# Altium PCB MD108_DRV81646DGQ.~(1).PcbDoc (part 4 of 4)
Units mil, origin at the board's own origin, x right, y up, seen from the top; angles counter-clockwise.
Board outline 6002 x 2931.52 mil, 4 copper layers (Top Layer, Mid-Layer 1, Mid-Layer 2, Bottom Layer), stack 92.712 mil thick; 251 components, 140 nets, 776 pads, 239 vias.
Unrouted connection lines stored in the file: 111.

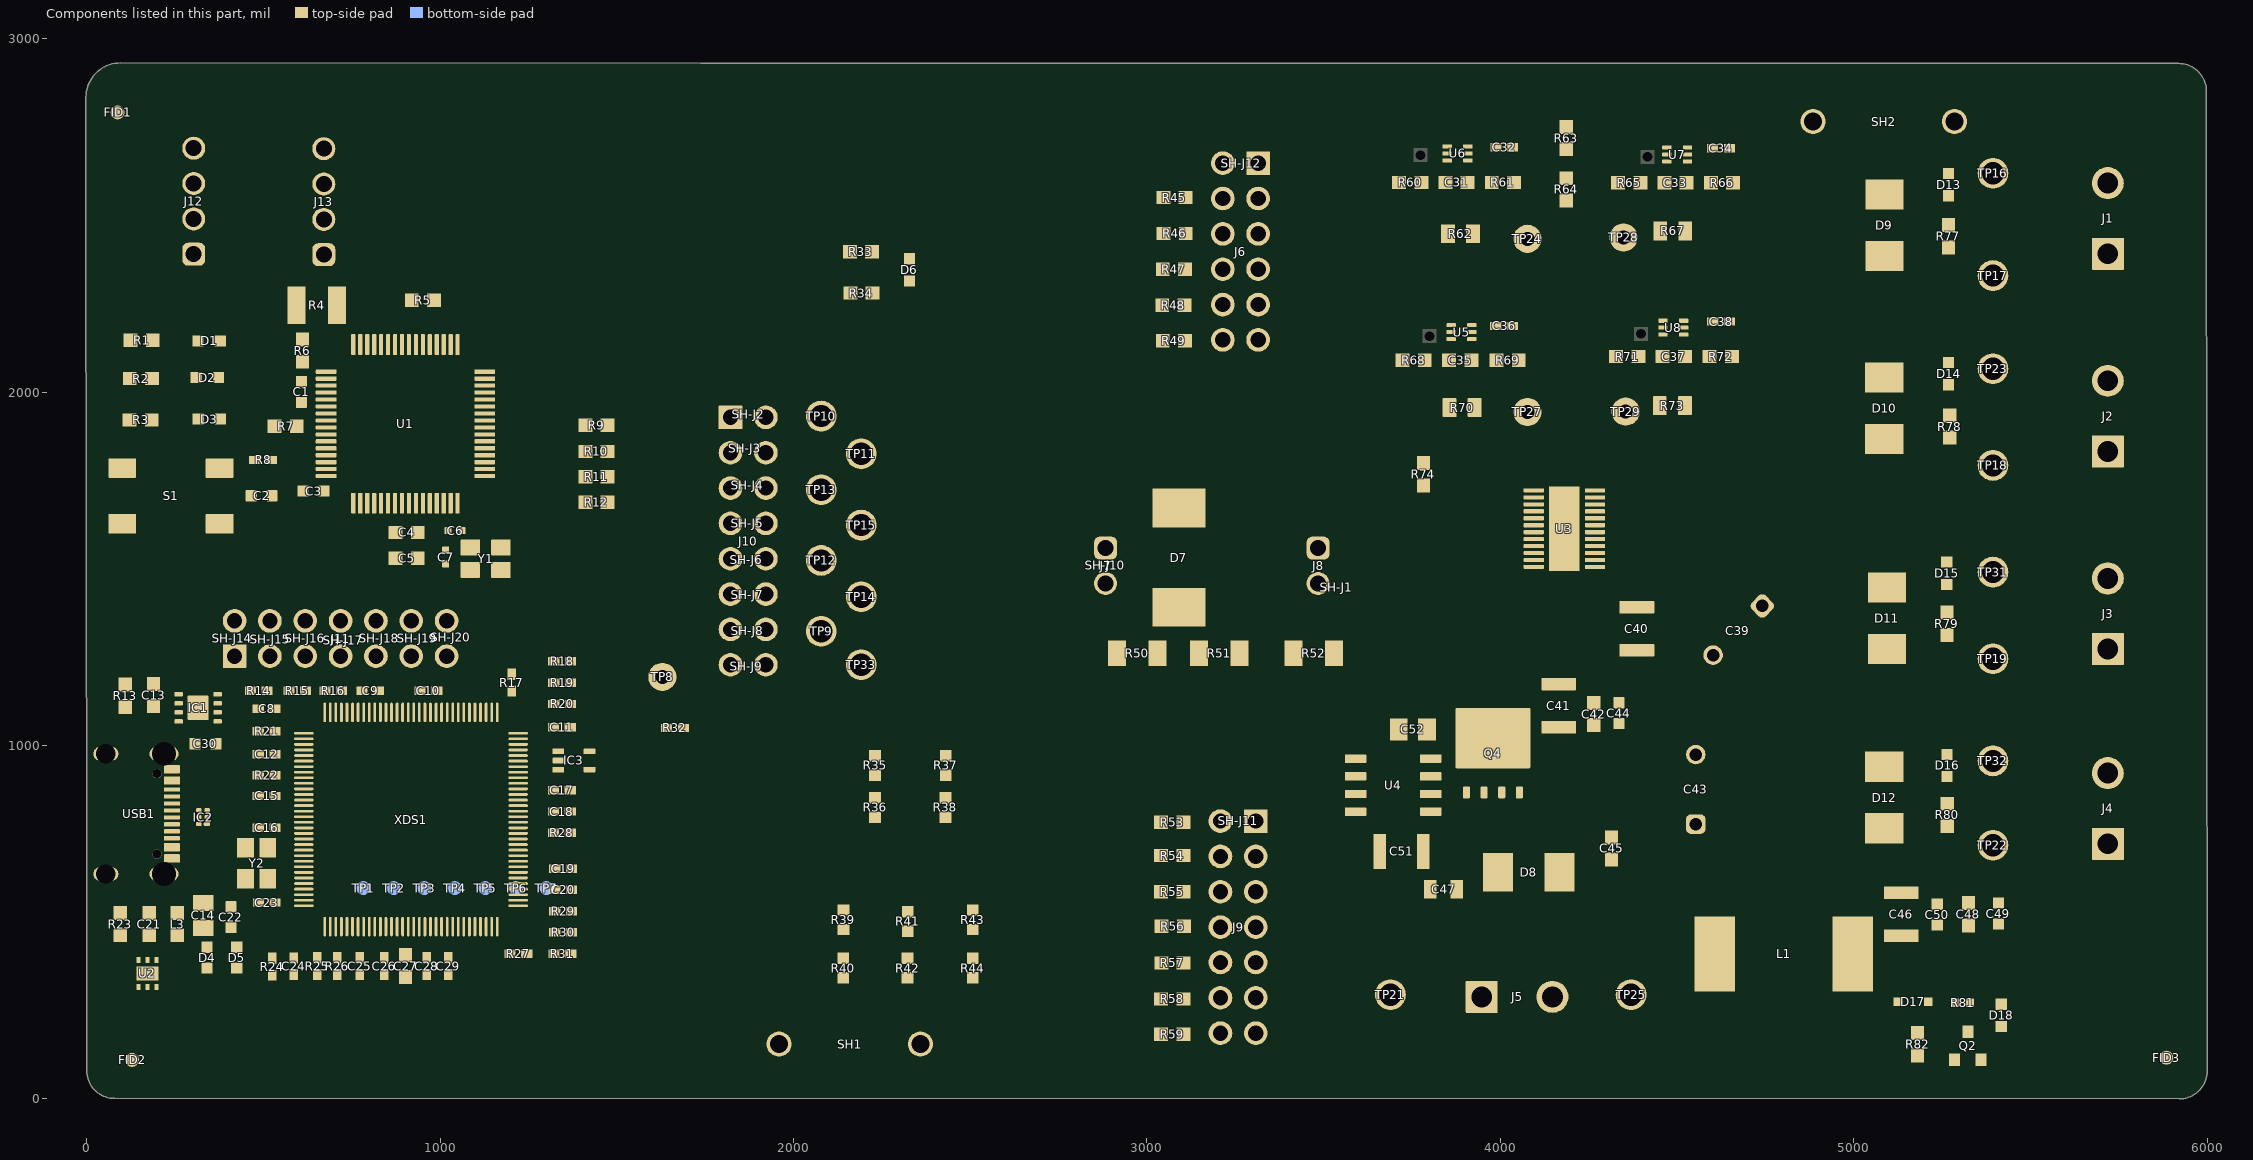
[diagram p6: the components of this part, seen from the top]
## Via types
v1: diameter 30, hole 16, Top Layer to Bottom Layer, tented both sides, 89 vias
v2: diameter 20, hole 8, Top Layer to Bottom Layer, tented both sides, 47 vias
v3: diameter 19.68, hole 7.87, Top Layer to Bottom Layer, tented both sides, 35 vias
v4: diameter 24, hole 12, Top Layer to Bottom Layer, tented both sides, 14 vias
v5: diameter 24, hole 7.87, Top Layer to Bottom Layer, tented both sides, 11 vias
v6: diameter 30, hole 15, Top Layer to Bottom Layer, tented both sides, 10 vias
v7: diameter 28, hole 14, Top Layer to Bottom Layer, tented both sides, 9 vias
v8: diameter 19.68, hole 7.87, Top Layer to Bottom Layer, 6 vias
v9: diameter 24, hole 8, Top Layer to Bottom Layer, tented both sides, 5 vias
v10: diameter 30, hole 14, Top Layer to Bottom Layer, tented both sides, 4 vias
v11: diameter 24, hole 11.81, Top Layer to Bottom Layer, tented both sides, 4 vias
v12: diameter 36, hole 18.29, Top Layer to Bottom Layer, tented both sides, 2 vias
v13: diameter 30, hole 15.75, Top Layer to Bottom Layer, tented both sides, 2 vias
v14: diameter 34, hole 16, Top Layer to Bottom Layer, tented both sides, 1 vias

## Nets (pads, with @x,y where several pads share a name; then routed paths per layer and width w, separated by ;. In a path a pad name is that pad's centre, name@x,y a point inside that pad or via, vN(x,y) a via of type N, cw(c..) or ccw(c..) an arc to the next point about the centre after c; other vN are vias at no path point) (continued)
copper on no net:
  other v2: 659.61,555.57 658.61,624.57

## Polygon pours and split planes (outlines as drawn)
GND on Top Layer "TOP_LAYER_GND_P439" (solid, remove dead copper, pour order 439): -13.71,2930.49 5964.99,2930.49 5964.99,-4.44 5948.53,-20.91 5936.7,-9.09 -35.01,-9.09 -35.01,2956.1
XDS_VCC on Top Layer "TOP_LAYER_XDS_VCC_P437" (solid, remove dead copper, pour order 437): 334.81,113.75 375.02,76.57 397.07,76.57 1314.1,76.57 1370.1,132.57 1370.1,334.15 1505.6,334.15 1548.02,376.57 1544.02,380.57 1544.02,1275.57 334.81,1275.57
VBAT on Top Layer "TOP_LAYER_VBAT_P436" (solid, remove dead copper, pour order 436): 3858.01,798.22 3770.91,798.54 3770.28,825.45 3857.82,825.45 3857.82,903.99 4032.52,903.99 4032.52,96.59 3857.82,96.59
no net on Top Layer "TOP_LAYER_NONET_P435" (solid, remove dead copper, pour order 435): 561.98,1466.48 567.61,1472.12 567.61,1611.68 481.47,1611.68 453.04,1583.25 453.04,1466.48
RSLEW/CNTL_GND/HiZ/VDD on Top Layer "TOP_LAYER_RSLEW/CNTL_GND/HIZ/VDD_P434" (solid, remove dead copper, pour order 434): 1451.8,1933.34 1500.73,1933.34 1500.73,1666.3 1451.8,1666.3
3V3_MCU on Top Layer "TOP_LAYER_3V3_MCU_P433" (solid, remove dead copper, pour order 433): 349.91,1879.24 349.07,1880.08 349.07,1948.64 427.42,1948.64 427.42,1899.21 407.45,1879.24 349.27,1879.24
OUT1 on Top Layer "TOP_LAYER_OUT1_P432" (solid, remove dead copper, pour order 432): 5932.98,2460.76 5931.09,2458.86 5356.79,2458.86 5337.83,2439.91 4941.64,2436.66 4875.32,2370.34 4875.04,2265.21 4875.32,2261.57 4875.36,2257.95 4865.14,2175.94 4472.34,1772.53 4474.36,1711.78 4431.43,1663.93 4455.21,1652.83 4494.59,1695.6 4545.21,1692.56 4987.74,2132.16 4989.58,2175.39 4992.93,2254.2 5931.09,2257.95 5931.09,2453.18 5932.98,2455.07
OUT2 on Top Layer "TOP_LAYER_OUT2_P430" (solid, remove dead copper, pour order 430): 5931.41,1930.74 5929.51,1928.85 5355.21,1928.85 5336.26,1909.89 4931.69,1906.57 4641.25,1722.03 4530.3,1642.71 4448.32,1643.7 4450.7,1616.41 4522.08,1615.64 4648.75,1616.69 4688.95,1627.78 4788.15,1674.34 4866.2,1727.94 4873.78,1727.94 5929.51,1727.94 5929.51,1923.16 5931.41,1925.06
OUT3 on Top Layer "TOP_LAYER_OUT3_P429" (solid, remove dead copper, pour order 429): 5933.38,1369.76 5931.49,1367.86 5357.19,1367.86 5338.23,1348.91 5061.86,1353.05 5010.83,1392.95 4926.82,1488.09 4785.08,1618.7 4670.73,1614.18 4363.89,1614.18 4363.89,1577.93 4638.41,1576.13 4899.49,1309.95 4875.72,1279.34 4875.72,1203.04 4875.44,1203.32 4926.82,1166.95 5931.49,1166.95 5931.49,1362.18 5933.38,1364.07
OUT4 on Top Layer "TOP_LAYER_OUT4_P395" (solid, remove dead copper, pour order 395): 5940.62,828.8 5938.73,826.9 5364.43,826.9 5345.47,807.95 5177.4,807.66 4525.71,1581.53 4413.98,1581.53 4414.9,1559.43 4621.1,1299.44 4931.54,786.95 4931.54,667.96 5022.97,625.99 5938.73,625.99 5938.73,821.21 5940.62,823.11
PI_IN on Top Layer "TOP_LAYER_PI_IN_P392" (solid, remove dead copper, pour order 392): 4153.62,953.28 3764.87,953.28 3764.87,1118.37 4103.75,1114.49 4116.16,1084.38 4141.08,1085.43 4348.7,1084.38 4348.7,869.54 4585.45,862.76 4703.77,778.73 4703.77,268.87 4675.69,240.79 4674.04,242.44 4522.11,242.44 4522.11,678.43 4470.91,729.62 4153.62,729.62
VM on Top Layer "TOP_LAYER_VM_P389" (solid, remove dead copper, pour order 389): 4941.98,511.49 4949.02,511.49 5695,511.49 5695,311.71 5682.83,299.55 4935.58,299.55 4935.58,508.29 4941.98,514.7 4942.62,514.7
no net on Top Layer "TOP_LAYER_NONET_P388" (solid, remove dead copper, pour order 388): 5087.71,604.14 5085.71,604.14 5447.49,604.14 5447.49,529.45 5441.36,523.33 5435.85,528.84 5082.65,528.84 5082.65,603.52 5082.04,604.14 5088.77,604.14
GND on Mid-Layer 2 "MID-LAYER_2_GND_P438" (solid, remove dead copper, pour order 438): -2.48,15.85 -2.48,2931.38 5997.52,2931.38 5997.52,15.85
VM on Mid-Layer 2 "MID-LAYER_2_VM_P427" (solid, remove dead copper, pour order 427): 5035.66,911.02 5034.64,910 4755.89,910 4755.89,1026.46 5086.33,1026.46 5094.19,1034.32 5094.19,911.02 5036.49,911.02 5035.66,911.85
VM on Bottom Layer "BOTTOM_LAYER_VM_P408" (solid, remove dead copper, pour order 408): 5485.78,2702.64 5486.92,2701.5 5650.26,2701.5 5650.26,306.86 5643.46,300.05 5642.32,301.18 5488.05,301.18 5488.05,2699.23 5486.92,2700.37
GND on Bottom Layer "BOTTOM_LAYER_GND_P413" (solid, remove dead copper, pour order 413): -26.36,2962.01 5965.24,2962.01 5973.64,2970.42 5973.64,-16.53 -26.36,-16.53
3V3_MCU on Mid-Layer 1 "MID-LAYER_1_3V3_MCU_P401" (solid, remove dead copper, pour order 401): 1685.54,1312.16 1749.88,1312.12 1750.94,1887.98 1864.7,1886.86 1867.24,1971.02 1654.9,1968.19 1654.9,1444.4 1442.8,1444.4 1245.24,1444.4 576.37,1444.4 580.16,1908.27 576.37,1908.27 507.13,1965.83 36.1,1964.87 36.1,1430.53 154.46,1312.16
GND on Mid-Layer 1 "MID-LAYER_1_GND_P421" (solid, remove dead copper, pour order 421): -33.06,-33.22 -33.06,2906.78 5966.94,2906.78 5966.94,-33.22

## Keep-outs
Keep-Out Layer:
  lines w20: -5.09,2930 5994.91,2930 6000,0 0,0 0,613.39 0,939.17 0,2930
  text ".Layer_Name" at 563.61,-858.49 h60

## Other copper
Top Layer:
  region net XDS_VCC: 1070.97,434.31 1063.97,434.31 1063.97,594.25 1066.81,594.25 1070.97,594.25 1070.97,496.56
  region net XDS_VCC: 1144.61,779.57 1167.61,779.57 1214.61,779.57 1214.61,785.57 1213.61,786.57 1144.61,786.57
  region net XDS_VCC: 1220.61,967.57 1144.61,967.57 1144.61,975.57 1220.61,975.57
  region net XDS_VCC: 1220.61,936.57 1144.61,936.57 1144.61,944.57 1146.61,944.57 1220.61,944.57
  region net XDS_VCC: 1144.61,637.57 1166.61,637.57 1273.61,637.57 1273.61,664.57 1273.61,660.57 1267.61,660.57 1144.61,660.57
  pour cut-out: 492.09,368.44 664.43,368.44 664.43,545.35 492.09,545.35
  pour cut-out: 1161.61,442.57 740.61,442.57 740.61,525.57 747.61,532.57 1160.61,532.57 1161.61,531.57
  pour cut-out: 659.61,626.57 659.61,940.57 569.61,940.57 569.61,639.57 582.61,626.57
  pour cut-out: 1193.61,544.57 1263.69,544.57 1266.67,547.55 1266.61,547.61 1266.61,1048.57 1259.61,1055.57 1188.61,1055.57 1175,1041.95 1175,557.16
  region net XDS_VCC: 929.61,471.51 929.61,551.57 921.61,551.57 921.61,471.51
  region net XDS_VCC: 611.61,810.57 611.61,818.57 714.61,818.57 714.61,811.57 714.61,810.57
  pour cut-out: 413.54,661.1 468.16,661.1 459.74,669.53 459.74,676.6 413.54,676.6
  region net XDS_VCC: 937.61,1096.57 937.61,1001.57 944.61,1001.57 944.61,1096.57
  region net XDS_VCC: 1063.61,1096.57 1063.61,995.57 1070.61,995.57 1070.61,1096.57
  region net XDS_VCC: 858.61,1001.57 882.61,1001.57 882.61,1166.57 858.61,1166.57
  pour cut-out: 1182.61,1117.57 1182.61,1060.87 1168.95,1048.57 824.61,1048.57 824.61,1140.57 1169.61,1140.57
  text ".Layer_Name" at 563.61,-858.49 h60
Mid-Layer 1:
  pour cut-out: 403.61,544.57 403.61,791.57 538.61,791.57 538.61,740.34 578.34,740.34 586.61,732.07 586.61,606.57 577.61,597.57 538.61,597.57 538.61,544.57
Mid-Layer 2:
  pour cut-out: 403.61,544.57 537.61,544.57 538.61,545.57 538.61,597.57 577.61,597.57 586.61,606.57 586.61,732.06 578.34,740.34 538.61,740.34 538.61,791.57 403.61,791.57
Bottom Layer:
  text ".Layer_Name" at 563.61,-858.49 h60

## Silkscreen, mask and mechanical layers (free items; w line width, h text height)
Top Overlay:
  drawing of 1235 lines, arcs and shapes, not listed
  text "GND" at 4742.54,2813.6 h106.3
  text "AUXILARY PINOUTS" at 152.04,2798.29 h60
  text "DRV81646DGQ" at 1949.61,2778.7 h80
  text "CSA 3" at 4288.24,2775.8 h60
  text "CSA 2" at 3667.03,2771.86 h60
  text "MSPM0" at 1516.1,2741.76 h80
  text "Cut Off Delay / INRUSH" at 2650.85,2741.31 h65
  text "VM" at 5351.48,2696.87 h70
  text "PB24" at 386.48,2663.6 h59.06
  text "PB13" at 788.92,2661.85 h59.06
  text "INRUSH" at 2684.64,2639.68 h60
  text "(OUT1)" at 4969.67,2634.19 h60
  text "PB25" at 386.48,2569.91 h59.06
  text "PB12" at 788.92,2568.16 h59.06
  text "DISABLED" at 2664.34,2525.61 h60
  text "nFAULT LED" at 2077.59,2522.05 h60
  text "DRV81646DGQEVM" at 1011.5,2483.86 h120
  text "PA0" at 386.48,2462.17 h59.06
  text "PB11" at 788.92,2460.42 h59.06
  text "0.5 ms" at 2664.48,2430.56 h60
  text "SRC2" at 3661.34,2408.93 h59.06
  text "SRC3" at 4551.72,2406.18 h59.06
  text "OUT1" at 5319.12,2405.32 h70
  text "PA1" at 386.48,2362.24 h59.06
  text "PB10" at 788.92,2360.49 h59.06
  text "MD108.PCB_Rev" at 1223.49,2352.95 h108.27
  text "1 ms" at 2664.48,2316.49 h60
  text "CSA 4" at 4283.04,2279.01 h60
  text "CSA 1" at 3677.28,2273.39 h60
  text "LED STATUS" at 40.94,2233.41 h60
  text "1.5 ms" at 2664.48,2207.85 h60
  text "OUT1" at 5483.29,2184.19 h100
  text "MCU_STATUS" at 93.8,2170.54 h30
  text "VM" at 5351.48,2137.57 h70
  text "2 ms" at 2664.48,2110.08 h60
  text "(OUT2)" at 4965.74,2089.68 h60
  text "GUI_STATUS" at 105.58,2078.93 h30
  text "3V3_STATUS" at 109.44,1965.67 h30
  text "3V3" at 2270.42,1917.19 h98.43
  text "SRC4" at 4556.72,1914.36 h59.06
  text "SRC1" at 3669.3,1907.06 h59.06
  text "DECAY MODES" at 2795.9,1900.5 h60
  text "OUT2" at 5329.87,1867.44 h70
  text "VCLAMP" at 3189.04,1805.81 h30
  text "nFAULT" at 2267.76,1794.15 h98.43
  text "FAST" at 2805.43,1787.62 h100
  text "SLOW" at 3397.43,1787.62 h100
  text "SDI/IN1" at 2270.42,1691.81 h98.43
  text "OUT2" at 5483.29,1628.22 h100
  text "SCLK/IN2" at 2271.85,1585.28 h98.43
  text "VM" at 5349.1,1563.99 h70
  text "(OUT3)" at 4962.21,1497.71 h60
  text "nSCS/IN3" at 2270.64,1477.34 h98.43
  text "NRST" at 1368.35,1421.15 h80 r90
  text "SWDIO" at 1448.78,1421.15 h80 r90
  text "SWCLK" at 1547.92,1421.15 h80 r90
  text "DRV81646" at 4028.98,1419.88 h40
  text "RXD>>" at 630.53,1411.86 h80 r90
  text "TXD <<" at 770.68,1408.57 h80 r90
  text "SDO/IN4" at 2271.75,1376.33 h98.43
  text "Target" at 1116.49,1324.37 h45
  text "OUT3" at 5331.06,1318.85 h70
  text "RSLEW/CNTL" at 2275.14,1273.35 h98.43
  text "Debugger" at 1099.6,1238.25 h45
  text "GND" at 2275.58,1179.22 h98.43
  text "GND" at 2869.9,1123.68 h30
  text "VM" at 3304.55,1122.06 h30
  text "OUT3" at 5483.29,1066 h100
  text "REVISION ID" at 2063.36,1048.16 h60
  text "VM" at 5351.48,1029.68 h70
  text "(OUT4)" at 4963.77,996.73 h60
  text "ILIM" at 2650.85,915.59 h60
  text "REV_ID1" at 2152.02,796.23 h50 r90
  text "REV_ID2" at 2348.35,793.33 h50 r90
  text "OUT4" at 5326.56,792.87 h70
  text "3 A" at 2647.45,754.58 h60
  text "2 A" at 2654.76,668.53 h60
  text "DEVICE ID" at 1963.31,599.4 h60
  text "1 A" at 2656.74,573.5 h60
  text "OUT4" at 5483.29,520.04 h100
  text "1.5 A" at 2658.72,486.38 h60
  text "0.75 A" at 2670.67,376.2 h60
  text "VM LED" at 5089.24,375.34 h60
  text "DEV_ID2" at 2247.32,341.85 h59.06 r90
  text "DEV_ID1" at 2055.1,339.5 h59.06 r90
  text "DEV_ID3" at 2429.1,340.34 h59.06 r90
  text "0.5 A" at 2672.41,271.6 h60
  text "0.25 A" at 2666.16,163.44 h60
  text "GND" at 1710.07,127.45 h106.3
  text "4.5V-65V DC" at 4519.59,88.16 h100
  text "GND" at 4265.93,65.56 h137.8
  text "VBAT" at 3523.59,65.48 h137.8
  text "VM" at 2032.4,-200.22 h30
  text ".Layer_Name" at 891.58,-858.49 h60
Bottom Overlay:
  lines w10: 3423.97,92.93 4602.25,92.93 4602.25,1045.23 3423.97,1045.23 3423.97,92.93
  text "VM" at 5368.99,2694.27 h30
  text "SRC3" at 4413.58,2469.73 h30
  text "SRC2" at 4122.74,2465.21 h30
  text "OUT1" at 5344.47,2399.61 h30
  text "VM" at 5372.74,2134.47 h30
  text "SRC1" at 4134.79,1967.92 h30
  text "SRC4" at 4413.38,1964.55 h30
  text "3V3" at 2170.32,1930.98 h30
  text "OUT2" at 5344.47,1860.7 h30
  text "nFAULT" at 2321.24,1807.86 h30
  text "SDI/IN1" at 2157.42,1712.54 h30
  text "SCLK/IN2" at 2313.36,1613.18 h30
  text "VM" at 5369.26,1555 h30
  text "nSCS/IN3" at 2180.25,1509 h30
  text "SDO/IN4" at 2321.18,1398.21 h30
  text "OUT3" at 5342.16,1307.89 h30
  text "RSLEW/CNTL" at 2181.1,1303.83 h30
  text "VM" at 5366.94,1027.68 h30
  text "OUT4" at 5347.44,783.73 h30
  text "GND" at 799.61,551.56 h50 r90
  text "ITMS" at 885.61,551.57 h50 r90
  text "ITCK" at 971.61,551.57 h50 r90
  text "ITDO" at 1058.61,551.57 h50 r90
  text "ITDI" at 1144.61,551.57 h50 r90
  text "IRSTN" at 1232.61,551.57 h50 r90
  text "XDS_VCC" at 1325.61,551.57 h50 r90
  text "Quick Start / 1. Connect USB, VM, GND, and Load / 2. Open GUI at dev.ti.com/gallery / 3. In the GUI start running each channel." at 3725.19,3.68 h30
  text ".Layer_Name" at 563.61,-858.49 h60
Top Paste:
  text ".Layer_Name" at 563.61,-858.49 h60
Bottom Paste:
  text ".Layer_Name" at 563.61,-858.49 h60
Top Solder:
  text ".Layer_Name" at 563.61,-858.49 h60
  text ".Layer_Name" at 563.61,-858.49 h60
Bottom Solder:
  text ".Layer_Name" at 563.61,-858.49 h60
Drill Guide:
  text ".Layer_Name" at 563.61,-858.49 h60
M1 Board Outline:
  lines w10: 5610.86,2925.07 5918.68,2925.07 ; 5619.56,2925.37 95.27,2931.53 ccw(c95.27,2834.26) -2,2834.26 -2,2516.61 0,675.71 0,613.39 0,80 ccw(c78.74,80) 78.74,1.26 5921.26,0.02 ccw(c5921.26,78.76) 6000,78.76 5998,2851.26 ; 5919.7,2926.62 cw(c5919.7,2847.88) 5998.44,2847.88
  text ".Layer_Name" at 563.61,-858.49 h60
M2 Board Dimensions:
  rectangle: -13.39,-275 111.61,-150
  rectangle: 111.61,-400 486.61,-275
  lines w7: -13.39,-275 986.61,-275 ; 111.61,-400 111.61,-150 ; 236.61,-400 236.61,-150 ; 486.61,-400 486.61,-150 ; 736.61,-400 736.61,-150 ; -13.39,-400 986.61,-400 986.61,-150 -13.39,-150 -13.39,-400
  text ".Layer_Name" at 563.61,-858.49 h60
M3 3D STEP Top:
  text ".Layer_Name" at 563.61,-858.49 h60
M4 3D STEP Bottom:
  text ".Layer_Name" at 563.61,-858.49 h60
M5 Assembly Top:
  lines w10: -305.39,-930.17 6294.61,-930.17 ; -305.39,-726.83 6296.61,-726.83 ; -305.39,-523.5 -305.39,-1133.5 3699.61,-1133.5 6296.61,-1133.5 6296.61,-523.5 -304.89,-523.5 -304.89,-1133.5 1270.61,-1133.5 ; 2159.61,-1133.5 2159.61,-523.5 ; 3426.61,-726.83 3426.61,-523.5 ; 4266.61,-726.83 4266.61,-523.5 ; 4888.61,-1140 4888.61,-937.17
  text "COMPONENTS MARKED 'DNP' SHOULD NOT BE POPULATED." at 1140.11,-318.5 h60
  text "ASSEMBLY VARIANT:" at 1139.61,-434 h60
  text ".VariantName" at 2175.61,-434 h60
  text "PCB VIEWED FROM TOP SIDE" at -241.89,-655.67 h60
  text "BOARD #:" at 2234.61,-655.67 h60
  text ".PRJ_Number" at 2780.11,-655.67 h60
  text "REV:" at 3624.61,-655.67 h60
  text ".PCB_Rev" at 3916.11,-655.67 h60
  text "SVN REV:" at 4462.61,-655.67 h60
  text ".VersionControl_RevNumber" at 4968.61,-655.67 h60
  text "TID #:" at 2234.61,-859 h60
  text ".TID" at 2780.11,-859 h60
  text "PLOT NAME =" at -241.89,-1064.34 h60
  text ".plot_File_Name" at 563.61,-1064.34 h60
  text "GENERATED    :" at 2236.61,-1064.34 h60
  text ".Print_Date" at 3106.11,-1064.34 h60
  text ".Print_Time" at 3835.11,-1064.34 h60
  text "TEXAS INSTRUMENTS" at 5099.61,-1064.34 h60
M6 Assembly Bottom:
  lines w10: -305.89,-727.33 6296.11,-727.33 ; -303.89,-930.67 6296.11,-930.67 ; 1102.11,-1140.5 1102.11,-937.67 ; 1724.11,-727.33 1724.11,-524 ; 2564.11,-727.33 2564.11,-524 ; 3831.11,-1134 3831.11,-524 ; 4720.11,-1134 6295.61,-1134 6295.61,-524 -305.89,-524 -305.89,-1134 2291.11,-1134 6296.11,-1134 6296.11,-524
  text "COMPONENTS MARKED 'DNP' SHOULD NOT BE POPULATED." at 6088.61,-318 h60
  text ".VersionControl_RevNumber" at 10567,-373 h60
  text ".VariantName" at 5044.61,-434 h60
  text "ASSEMBLY VARIANT:" at 6083.61,-434 h60
  text "SVN REV:" at 1528.11,-656.17 h60
  text ".PCB_Rev" at 2074.61,-656.17 h60
  text "REV:" at 2366.11,-656.17 h60
  text ".PRJ_Number" at 3210.61,-656.17 h60
  text "BOARD #:" at 3756.11,-656.17 h60
  text "PCB VIEWED FROM BOTTOM SIDE" at 6232.61,-656.17 h60
  text ".TID" at 3210.61,-859.5 h60
  text "TID #:" at 3756.11,-859.5 h60
  text "TEXAS INSTRUMENTS" at 891.11,-1064.84 h60
  text ".Print_Time" at 2155.61,-1064.84 h60
  text ".Print_Date" at 2884.61,-1064.84 h60
  text "GENERATED    :" at 3754.11,-1064.84 h60
  text ".plot_File_Name" at 5427.11,-1064.84 h60
  text "PLOT NAME =" at 6232.61,-1064.84 h60
M9 Title Sheet:
  drawing of 57 lines, arcs and shapes, not listed
  text "1" at 726.45,8036.5 h70
  text "2" at 3222.11,8036.5 h70
  text "3" at 5711.46,8036.5 h70
  text "4" at 8218.13,8036.5 h70
  text "5" at 10717.11,8036.5 h70
  text "6" at 13222.11,8036.5 h70
  text "A" at -429.89,6893.5 h70
  text "A" at 14370.11,6893.5 h70
  text "B" at -429.89,4513.5 h70
  text "B" at 14370.11,4513.5 h70
  text "C" at -429.89,2138.5 h70
  text "C" at 14370.11,2138.5 h70
  text "PROJECT TITLE:" at 11330.11,277.5 h45
  text ".PRJ_Title" at 11380.11,144.17 h70
  text "DESIGNED FOR:" at 11330.11,-23.5 h45
  text ".PRJ_Customer" at 11380.11,-163.5 h70
  text "D" at -429.89,-231.5 h70
  text "D" at 14370.11,-231.5 h70
  text "FILE NAME:" at 11330.11,-323.5 h45
  text ".PCB_File_Name_No_Path" at 11380.11,-443.5 h70
  text "Texas Instruments (TI) and/or its licensors do not warrant the accuracy or completeness of this specification" at 6360.61,-605.34 h45
  text "ENGINEER:" at 11330.11,-613.5 h45
  text "LAYOUT BY:" at 12835.11,-613.5 h45
  text "or any information contained therein. TI and/or its licensors do not warrant that this design will meet" at 6315.63,-718 h45
  text ".PRJ_Engineer" at 11380.11,-768.49 h70
  text ".PCB_Layout" at 12885.61,-768.49 h70
  text "the specifications, will be suitable for your application or fit for any particular purpose, or will operate in" at 6315.63,-830.67 h45
  text ".Layer_Name" at 563.61,-858.49 h60
  text "ALTIUM DESIGNER VERSION:" at 12835.11,-923.5 h45
  text "an implementation. TI and/or its licensors do not warrant that the design is production worthy. You should" at 6315.63,-943.33 h45
  text "completely validate and test your design implementation to confirm the system functionality for your application." at 6360.61,-1056 h45
  text ".print_Scale" at 11380.11,-1056.83 h70
  text ".Application_BuildNumber" at 12885.61,-1056.83 h70
  text "1" at 726.45,-1263.5 h70
  text "2" at 3222.11,-1263.5 h70
  text "3" at 5711.46,-1263.5 h70
  text "4" at 8218.13,-1263.5 h70
  text "5" at 10717.11,-1263.5 h70
  text "6" at 13222.11,-1263.5 h70
M10 Fab Notes:
  drawing of 189 lines, arcs and shapes, not listed
  text "DESIGN INFORMATION" at 12368.63,6356.17 h60
  text "MIN. TRACK WIDTH:" at 11724.07,6224.05 h60
  text "8" at 12820.32,6224.05 h60
  text "MIL" at 12975.07,6224.05 h60
  text "7.874" at 12653.94,6102.36 h60
  text "MIN. CLEARANCE:" at 11724.07,6099.92 h60
  text "MIL" at 12975.07,6099.92 h60
  text "MIN. VIA PAD SIZE:" at 11724.07,5975.8 h60
  text "24" at 12790.33,5975.8 h60
  text "MIL" at 12975.07,5975.8 h60
  text "0.05mm (2MIL)" at 12419.07,5845.9 h60
  text "MINIMUM ANNULAR RING" at 11394.84,5837.67 h60
  text "EXTERNAL" at 13127.07,5837.67 h60
  text "PER" at 11594.84,5727.55 h60
  text "IPC-D-275 CLASS 2 LEVEL C" at 11814.84,5727.54 h60
  text "MIL, HOLES" at 13303.07,5627.07 h60
  text "+/-" at 12910.61,5618.48 h60
  text "+/-" at 13764.61,5618.48 h60
  text "REGISTRATION TOLERANCES:" at 11394.84,5617.42 h60
  text "METAL" at 12594.61,5617.42 h60
  text "5" at 13170.82,5617.42 h60
  text "3" at 14003.82,5617.42 h60
  text "MIL" at 14120.07,5617.42 h60
  text "HOLE SIZE TOLERANCE (UNLESS OTHERWISE SPECIFIED):" at 11394.84,5519.1 h60
  text "+/-" at 13764.61,5516.23 h60
  text "3" at 14003.82,5515.17 h60
  text "MIL" at 14120.07,5515.17 h60
  text "MATERIAL:" at 11320.07,5377.52 h60
  text "FR-4 High Tg" at 12306.52,5249 h60
  text "X" at 12162.08,5241.01 h60
  text "FR-4" at 11741.08,5236.49 h60
  text "OTHER" at 13229.07,5236.49 h60
  text "62 MIL (1.6mm) +/-10%" at 12061.18,5093.46 h60
  text "X" at 11941.08,5091.01 h60
  text "THICKNESS:" at 11394.84,5085.24 h60
  text "OTHER" at 13346.07,5085.24 h60
  text "TOLERANCE:" at 11394.84,4946.92 h60
  text "X" at 12243.08,4946.92 h60
  text "ANSI IPC-6012 TYPE 3 CLASS 2" at 12421.09,4946.92 h60
  text "OTHER +/-" at 12421.07,4802.73 h60
  text "BOW & TWIST:" at 11394.84,4657.54 h60
  text "X" at 12243.08,4657.54 h60
  text "ANSI IPC-6012 TYPE 3 CLASS 2" at 12421.09,4657.54 h60
  text "OTHER +/-" at 12421.07,4510.85 h60
  text "DRILLING:" at 11320.07,4380.23 h60
  text "NC_DRILL FILES" at 13081.07,4275.04 h60
  text "REFERENCE:" at 11394.84,4271.1 h60
  text "X" at 12052.08,4271.01 h60
  text "AS SHOWN" at 12230.07,4271.1 h60
  text "X" at 12953.08,4271.1 h60
  text "OTHER" at 13379.07,4128.85 h60
  text "PTH COPPER THICKNESS:" at 11394.52,4125.32 h60
  text "X" at 12533.76,4125.32 h60
  text "20-30 um" at 12661.75,4125.32 h60
  text "BOARD FINISH:" at 11320.07,3977.73 h60
  text "SILKSCREEN:" at 11475.3,3867.6 h60
  text "X" at 12433.08,3867.6 h60
  text "TOP" at 12550.07,3867.6 h60
  text "X" at 12943.08,3867.6 h60
  text "BOTTOM" at 13061.07,3867.6 h60
  text "SILKSCREEN COLOR:" at 11475.3,3712.41 h60
  text "X" at 12432.08,3712.41 h60
  text "WHITE" at 12550.07,3712.41 h60
  text "OTHER" at 13061.07,3712.41 h60
  text "X" at 12563.08,3568.96 h60
  text "GREEN" at 12681.07,3568.96 h60
  text "OTHER" at 13299.07,3568.96 h60
  text "SOLDER RESIST COLOR:" at 11475.3,3562.1 h60
  text "X" at 12563.08,3414.71 h60
  text "MATTE" at 12681.07,3414.71 h60
  text "SEMI-GLOSS" at 13298.61,3414.07 h60
  text "IMMERSION GOLD (ENIG)" at 12381.07,3241.94 h60
  text "ENEPIG" at 13718.61,3234.72 h60
  text "SURFACE FINISH:" at 11320.07,3233.72 h60
  text "X" at 12203.08,3233.72 h60
  text "IMM. TIN/SILVER OR EQUIV" at 11649.61,3096.4 h60
  text "OTHER" at 13081.07,3092.47 h60
  text "ARRAY/PANEL:" at 11320.07,2937.09 h60
  text "CUT AND TRIM PER M1 BOARD OUTLINE" at 12381.07,2928.87 h60
  text "N.C. ROUTE" at 12381.07,2792.9 h60
  text "X" at 13069.08,2792.9 h60
  text "V. SCORE" at 13247.07,2792.9 h60
  text "CERTIFICATION:" at 11320.07,2663.77 h60
  text "MATERIALS AND WORKMANSHIP FOR ALL PCBS" at 12045.07,2663.77 h60
  text "TO MEET OR EXCEED THE REQUIREMENTS OF:" at 12045.07,2569.71 h60
  text "X" at 11682.58,2441.08 h60
  text "ANSI IPC-A-600F CLASS ->" at 11810.58,2441.08 h60
  text "X" at 13458.58,2441.08 h60
  text "2" at 13568.58,2441.08 h60
  text "1" at 13253.58,2439.58 h60
  text "3" at 13922.58,2439.58 h60
  text "X" at 12494.58,2293.39 h60
  text "RoHS" at 12622.58,2293.39 h60
  text "OTHER" at 13266.98,2293.39 h60
  text "PER ORDER" at 13664.04,2293.39 h60
  text "ALL BOARDS MUST MEET OR EXCEED UL94-V0 REQUIREMENTS." at 11347.61,2139.57 h60
  text "PCB MUST BEAR THE UL94V-0 UL REGISTERED MATERIAL ID NUMBER" at 11347.61,2023.5 h60
  text "ADDITIONAL REQUIREMENTS:" at 11320.07,1854.08 h60
  text "MICROSECTION:" at 11394.84,1746.95 h60
  text "YES" at 12300.58,1746.95 h60
  text "REQUIRED" at 13162.07,1602.62 h60
  text "BARE BOARD ELEC. TEST:" at 11394.84,1599.76 h60
  text "NONE" at 12700.58,1599.76 h60
  text "X" at 13044.08,1599.76 h60
  text "PER ORDER" at 13754.07,1599.76 h60
  text "XX MIL VIAS REQUIRE NON-CONDUCTIVE FILL AND PLANARIZE" at 11562.99,1394.82 h59
  text "XX MIL VIAS REQUIRE CONDUCTIVE FILL AND PLANARIZE" at 11570.99,1290.84 h60
  text "OUTER XX MIL TRACES REQUIRE 50 OHM SINGLE-ENDED IMPEDANCE" at 11570.01,1127.46 h58
  text "LAYER 2 & 3 (INNER LAYERS) XX MIL WIDE, XX MIL SPACE / TRACES REQUIRE 100 OHM DIFFERENTIAL IMPEDANCE" at 11562.01,891.74 h60
  text ".Layer_Name" at 563.61,-858.49 h60
M11 Gerber Information:
  lines w10: -305.39,-930.17 6294.61,-930.17 ; -305.39,-726.83 6296.61,-726.83 ; -305.39,-523.5 -305.39,-1133.5 3699.61,-1133.5 6296.61,-1133.5 6296.61,-523.5 -304.89,-523.5 -304.89,-1133.5 1270.61,-1133.5 ; 2159.61,-1133.5 2159.61,-523.5 ; 3426.61,-726.83 3426.61,-523.5 ; 4266.61,-726.83 4266.61,-523.5 ; 4888.61,-1140 4888.61,-937.17
  text "ALL ARTWORK VIEWED FROM TOP SIDE" at -241.89,-655.67 h60
  text "BOARD #:" at 2234.61,-655.67 h60
  text ".PRJ_Number" at 2780.11,-655.67 h60
  text "REV:" at 3624.61,-655.67 h60
  text ".PCB_Rev" at 3916.11,-655.67 h60
  text "SVN REV:" at 4462.61,-655.67 h60
  text ".VersionControl_RevNumber" at 4968.61,-655.67 h60
  text "LAYER NAME =" at -241.89,-858.49 h60
  text "TID #:" at 2234.61,-859 h60
  text ".TID" at 2780.11,-859 h60
  text "PLOT NAME =" at -241.89,-1064.34 h60
  text ".plot_File_Name" at 563.61,-1064.34 h60
  text "GENERATED    :" at 2236.61,-1064.34 h60
  text ".Print_Date" at 3106.11,-1064.34 h60
  text ".Print_Time" at 3835.11,-1064.34 h60
  text "TEXAS INSTRUMENTS" at 5099.61,-1064.34 h60
M12 Stackup:
  drawing of 295 lines, arcs and shapes, not listed
  text "Layer" at 799.58,6113 h60
  text "Name" at 1209.49,6113 h60
  text "Material" at 2139.23,6113 h60
  text "Thickness" at 2999,6113 h60
  text "Constant" at 3648.84,6113 h60
  text "Board Layer Stack" at 4218.7,6113 h60
  text "Top Overlay" at 1209.49,5993 h60
  text "Top Solder" at 1209.49,5873 h60
  text "Solder Resist" at 2139.23,5873 h60
  text "0.40mil" at 2999,5873 h60
  text "3.5" at 3648.84,5873 h60
  text "1" at 799.58,5753 h60
  text "Top Layer" at 1209.49,5753 h60
  text "2.76mil" at 2999,5753 h60
  text "Dielectric1" at 1209.49,5633 h60
  text "FR-4 High Tg" at 2139.23,5633 h60
  text "59.20mil" at 2999,5633 h60
  text "4.8" at 3648.84,5633 h60
  text "2" at 799.58,5513 h60
  text "Mid-Layer 1" at 1209.49,5513 h60
  text "1.40mil" at 2999,5513 h60
  text "Dielectric2" at 1209.49,5393 h60
  text "FR-4" at 2139.23,5393 h60
  text "12.60mil" at 2999,5393 h60
  text "4.8" at 3648.84,5393 h60
  text "3" at 799.58,5273 h60
  text "Mid-Layer 2" at 1209.49,5273 h60
  text "1.40mil" at 2999,5273 h60
  text "Dielectric3" at 1209.49,5153 h60
  text "FR-4" at 2139.23,5153 h60
  text "12.60mil" at 2999,5153 h60
  text "4.8" at 3648.84,5153 h60
  text "4" at 799.58,5033 h60
  text "Bottom Layer" at 1209.49,5033 h60
  text "2.76mil" at 2999,5033 h60
  text "Bottom Solder" at 1209.49,4913 h60
  text "Solder Resist" at 2139.23,4913 h60
  text "0.40mil" at 2999,4913 h60
  text "3.5" at 3648.84,4913 h60
  text "Bottom Overlay" at 1209.49,4793 h60
  text ".Layer_Name" at 563.61,-858.49 h60
M13 Component Bodies Top:
  text ".Layer_Name" at 563.61,-858.49 h60
M14 Component Bodies Bottom:
  text ".Layer_Name" at 563.61,-858.49 h60
M15 Courtyards Top:
  text ".Layer_Name" at 563.61,-858.49 h60
M16 Courtyards Bottom:
  text ".Layer_Name" at 563.61,-858.49 h60
Drill Drawing:
  drawing of 177 lines, arcs and shapes, not listed
  text "Symbol" at 7504.94,4165.39 h72
  text "Count" at 7805.6,4165.39 h72
  text "Hole Size" at 8107.3,4165.39 h72
  text "Plated" at 8669.3,4165.39 h72
  text "Hole Type" at 8928.5,4165.39 h72
  text "Drill Layer Pair" at 9303.74,4165.39 h72
  text "Hole Tolerance" at 10028.29,4165.39 h72
  text "52" at 7805.6,4040.89 h60
  text "0.200mm (7.87mil)" at 8107.3,4040.89 h60
  text "PTH" at 8669.3,4040.89 h60
  text "Round" at 8928.5,4040.89 h60
  text "Top Layer - Bottom Layer" at 9303.74,4040.89 h60
  text "52" at 7805.6,3916.39 h60
  text "0.203mm (8.00mil)" at 8107.3,3916.39 h60
  text "PTH" at 8669.3,3916.39 h60
  text "Round" at 8928.5,3916.39 h60
  text "Top Layer - Bottom Layer" at 9303.74,3916.39 h60
  text "4" at 7805.6,3791.89 h60
  text "0.300mm (11.81mil)" at 8107.3,3791.89 h60
  text "PTH" at 8669.3,3791.89 h60
  text "Round" at 8928.5,3791.89 h60
  text "Top Layer - Bottom Layer" at 9303.74,3791.89 h60
  text "H" at 7479.63,3781.9 h55.33
  text "14" at 7805.6,3667.39 h60
  text "0.305mm (12.00mil)" at 8107.3,3667.39 h60
  text "PTH" at 8669.3,3667.39 h60
  text "Round" at 8928.5,3667.39 h60
  text "Top Layer - Bottom Layer" at 9303.74,3667.39 h60
  text "13" at 7805.6,3542.89 h60
  text "0.356mm (14.00mil)" at 8107.3,3542.89 h60
  text "PTH" at 8669.3,3542.89 h60
  text "Round" at 8928.5,3542.89 h60
  text "Top Layer - Bottom Layer" at 9303.74,3542.89 h60
  text "10" at 7805.6,3418.39 h60
  text "0.381mm (15.00mil)" at 8107.3,3418.39 h60
  text "PTH" at 8669.3,3418.39 h60
  text "Round" at 8928.5,3418.39 h60
  text "Top Layer - Bottom Layer" at 9303.74,3418.39 h60
  text "C" at 7479.63,3408.4 h55.33
  text "2" at 7805.6,3293.89 h60
  text "0.400mm (15.75mil)" at 8107.3,3293.89 h60
  text "PTH" at 8669.3,3293.89 h60
  text "Round" at 8928.5,3293.89 h60
  text "Top Layer - Bottom Layer" at 9303.74,3293.89 h60
  text "B" at 7479.63,3283.9 h55.33
  text "90" at 7805.6,3169.39 h60
  text "0.406mm (16.00mil)" at 8107.3,3169.39 h60
  text "PTH" at 8669.3,3169.39 h60
  text "Round" at 8928.5,3169.39 h60
  text "Top Layer - Bottom Layer" at 9303.74,3169.39 h60
  text "2" at 7805.6,3044.89 h60
  text "0.465mm (18.29mil)" at 8107.3,3044.89 h60
  text "PTH" at 8669.3,3044.89 h60
  text "Round" at 8928.5,3044.89 h60
  text "Top Layer - Bottom Layer" at 9303.74,3044.89 h60
  text "2" at 7805.6,2920.39 h60
  text "0.650mm (25.59mil)" at 8107.3,2920.39 h60
  text "NPTH" at 8669.3,2920.39 h60
  text "Round" at 8928.5,2920.39 h60
  text "Top Layer - Bottom Layer" at 9303.74,2920.39 h60
  text "4" at 7805.6,2795.89 h60
  text "0.700mm (27.56mil)" at 8107.3,2795.89 h60
  text "PTH" at 8669.3,2795.89 h60
  text "Round" at 8928.5,2795.89 h60
  text "Top Layer - Bottom Layer" at 9303.74,2795.89 h60
  text "A" at 7479.63,2785.9 h55.33
  text "4" at 7805.6,2671.39 h60
  text "0.900mm (35.43mil)" at 8107.3,2671.39 h60
  text "PTH" at 8669.3,2671.39 h60
  text "Round" at 8928.5,2671.39 h60
  text "Top Layer - Bottom Layer" at 9303.74,2671.39 h60
  text "5" at 7805.6,2546.89 h60
  text "1.016mm (40.00mil)" at 8107.3,2546.89 h60
  text "PTH" at 8669.3,2546.89 h60
  text "Round" at 8928.5,2546.89 h60
  text "Top Layer - Bottom Layer" at 9303.74,2546.89 h60
  text "56" at 7805.6,2422.39 h60
  text "1.100mm (43.31mil)" at 8107.3,2422.39 h60
  text "PTH" at 8669.3,2422.39 h60
  text "Round" at 8928.5,2422.39 h60
  text "Top Layer - Bottom Layer" at 9303.74,2422.39 h60
  text "F" at 7479.63,2412.4 h55.33
  text "12" at 7805.6,2297.89 h60
  text "1.150mm (45.28mil)" at 8107.3,2297.89 h60
  text "PTH" at 8669.3,2297.89 h60
  text "Round" at 8928.5,2297.89 h60
  text "Top Layer - Bottom Layer" at 9303.74,2297.89 h60
  text "4" at 7805.6,2173.39 h60
  text "1.300mm (51.18mil)" at 8107.3,2173.39 h60
  text "PTH" at 8669.3,2173.39 h60
  text "Round" at 8928.5,2173.39 h60
  text "Top Layer - Bottom Layer" at 9303.74,2173.39 h60
  text "2" at 7805.6,2048.89 h60
  text "1.400mm (55.12mil)" at 8107.3,2048.89 h60
  text "PTH" at 8669.3,2048.89 h60
  text "Slot" at 8928.5,2048.89 h60
  text "Top Layer - Bottom Layer" at 9303.74,2048.89 h60
  text "D" at 7479.63,2038.9 h55.33
  text "10" at 7805.6,1924.39 h60
  text "1.500mm (59.06mil)" at 8107.3,1924.39 h60
  text "PTH" at 8669.3,1924.39 h60
  text "Round" at 8928.5,1924.39 h60
  text "Top Layer - Bottom Layer" at 9303.74,1924.39 h60
  text "18" at 7805.6,1799.89 h60
  text "1.600mm (63.00mil)" at 8107.3,1799.89 h60
  text "PTH" at 8669.3,1799.89 h60
  text "Round" at 8928.5,1799.89 h60
  text "Top Layer - Bottom Layer" at 9303.74,1799.89 h60
  text "2" at 7805.6,1675.39 h60
  text "1.700mm (66.93mil)" at 8107.3,1675.39 h60
  text "PTH" at 8669.3,1675.39 h60
  text "Slot" at 8928.5,1675.39 h60
  text "Top Layer - Bottom Layer" at 9303.74,1675.39 h60
  text "E" at 7479.63,1665.4 h55.33
  text "358 Total" at 7805.6,1550.89 h60
  text "Slot definitions :" at 7504.94,1463.74 h60
  text "Routed Path Length" at 7955.59,1463.74 h60
  text "= Calculated from tool start centre position to tool end centre position." at 8495.44,1463.74 h60
  text "Hole Length" at 7955.59,1413.94 h60
  text "= Routed Path Length + Tool Size = Slot length as defined in the PCB layout" at 8295.59,1413.94 h60
  text ".Layer_Name" at 563.61,-858.49 h60
M17 Embedded Cavity:
  text ".Layer_Name" at 563.61,-858.49 h60
M18 Embedded Assembly:
  text ".Layer_Name" at 563.61,-858.49 h60
M19 Embedded Keepout:
  text ".Layer_Name" at 563.61,-858.49 h60

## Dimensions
-13.39,-400 to 986.61,-400 on M2 Board Dimensions
-13.39,0 to -2,2834.26 on M2 Board Dimensions
-13.39,0 to 0,675.71 on M2 Board Dimensions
